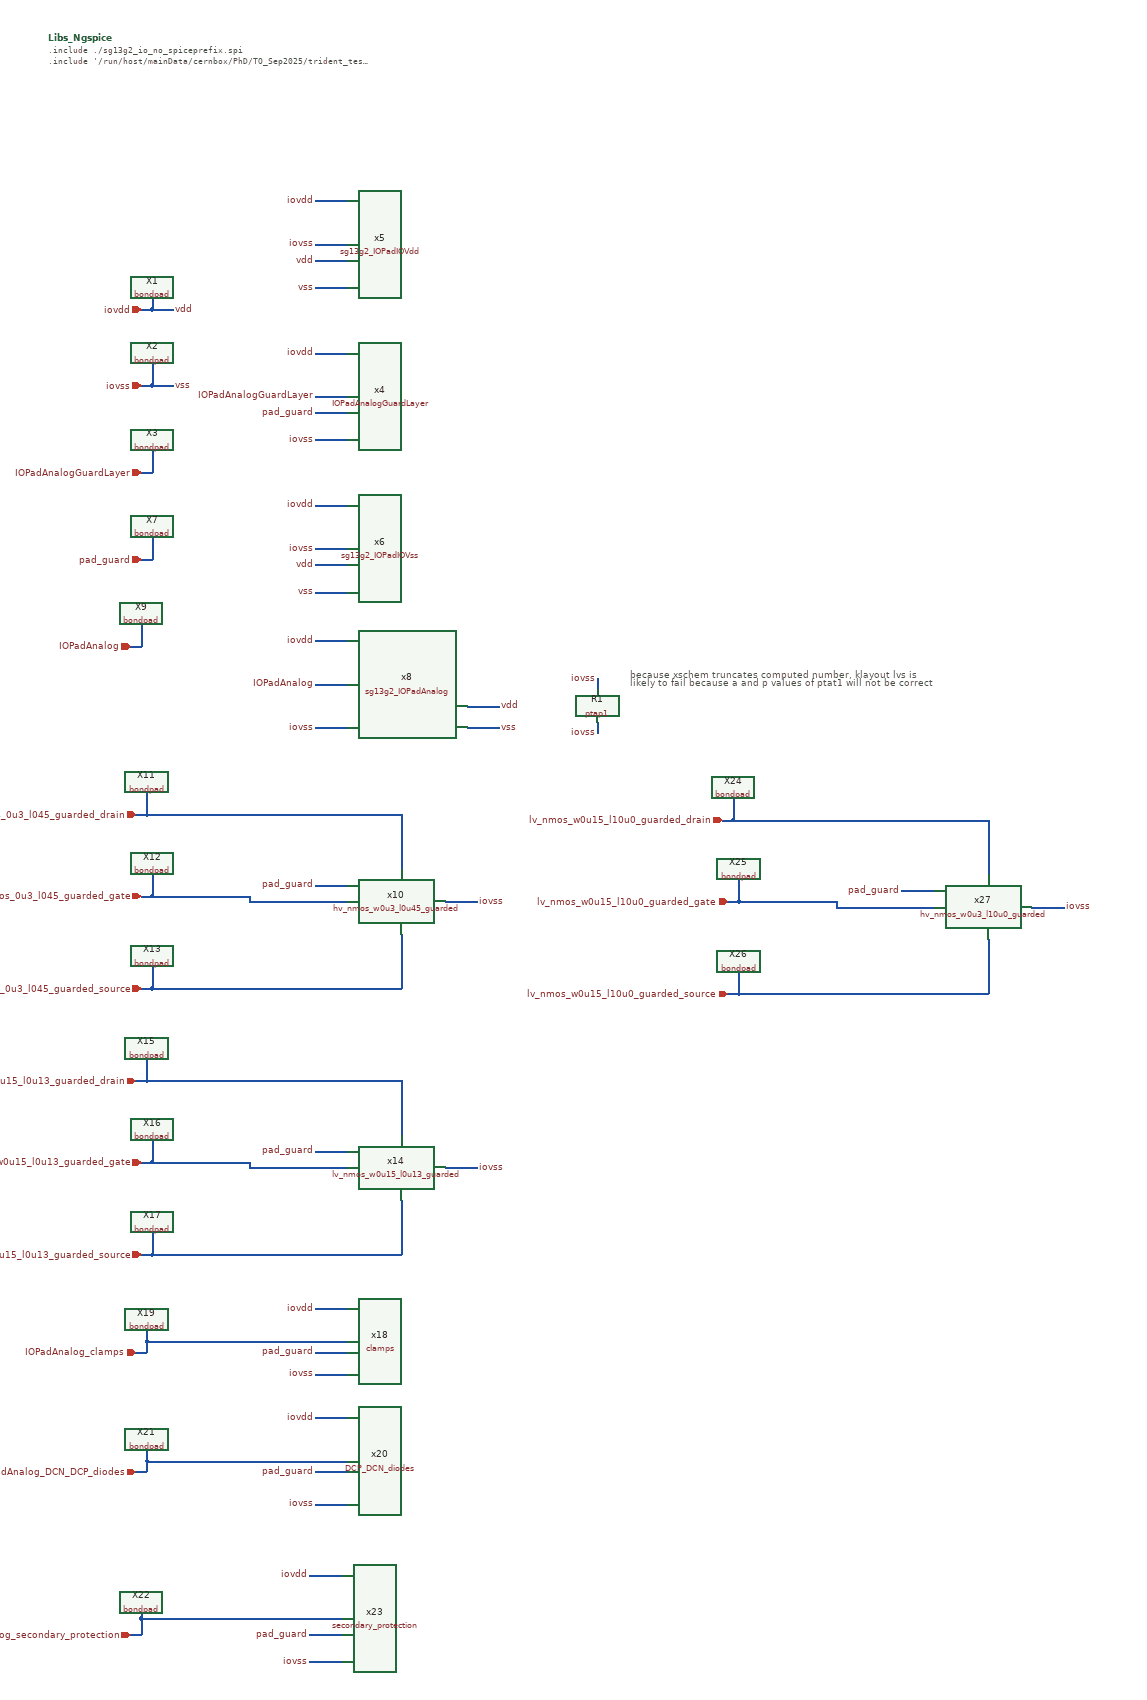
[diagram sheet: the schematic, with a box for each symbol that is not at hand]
v {xschem version=3.4.8RC file_version=1.2}
G {}
K {}
V {}
S {}
F {}
E {}
T {because xschem truncates computed number, klayout lvs is 
likely to fail because a and p values of ptat1 will not be correct} 800 500 0 0 0.4 0.4 {}
N -100 300 -80 300 {lab=pad_guard}
N -80 260 -80 300 {lab=pad_guard}
N -100 140 -80 140 {lab=IOPadAnalogGuardLayer}
N -80 100 -80 140 {lab=IOPadAnalogGuardLayer}
N -100 -20 -80 -20 {lab=iovss}
N -80 -60 -80 -20 {lab=iovss}
N -100 -160 -80 -160 {lab=iovdd}
N -80 -180 -80 -160 {lab=iovdd}
N 220 -360 280 -360 {lab=iovdd}
N 220 -80 280 -80 {lab=iovdd}
N 220 200 280 200 {lab=iovdd}
N 220 -280 280 -280 {lab=iovss}
N 220 80 280 80 {lab=iovss}
N 220 280 280 280 {lab=iovss}
N 220 -250 280 -250 {lab=vdd}
N 220 310 280 310 {lab=vdd}
N 220 -200 280 -200 {lab=vss}
N 220 360 280 360 {lab=vss}
N 220 -0 280 -0 {lab=IOPadAnalogGuardLayer}
N 220 30 280 30 {lab=pad_guard}
N -80 -20 -40 -20 {lab=iovss}
N -80 -160 -40 -160 {lab=iovdd}
N -120 460 -100 460 {lab=IOPadAnalog}
N -100 420 -100 460 {lab=IOPadAnalog}
N 220 450 280 450 {lab=iovdd}
N 220 610 280 610 {lab=iovss}
N 220 530 280 530 {lab=IOPadAnalog}
N 500 570 560 570 {lab=vdd}
N 500 610 560 610 {lab=vss}
N 740 600 740 620 {lab=iovss}
N 740 520 740 540 {lab=iovss}
N 460 930 520 930 {lab=iovss}
N 220 900 280 900 {lab=pad_guard}
N -110 770 -90 770 {lab=hv_nmos_0u3_l045_guarded_drain}
N -90 730 -90 770 {lab=hv_nmos_0u3_l045_guarded_drain}
N -100 920 -80 920 {lab=hv_nmos_0u3_l045_guarded_gate}
N -80 880 -80 920 {lab=hv_nmos_0u3_l045_guarded_gate}
N -100 1090 -80 1090 {lab=hv_nmos_0u3_l045_guarded_source}
N -80 1050 -80 1090 {lab=hv_nmos_0u3_l045_guarded_source}
N -90 770 380 770 {lab=hv_nmos_0u3_l045_guarded_drain}
N 380 770 380 870 {lab=hv_nmos_0u3_l045_guarded_drain}
N -80 1090 380 1090 {lab=hv_nmos_0u3_l045_guarded_source}
N 380 990 380 1090 {lab=hv_nmos_0u3_l045_guarded_source}
N -80 920 100 920 {lab=hv_nmos_0u3_l045_guarded_gate}
N 100 920 100 930 {lab=hv_nmos_0u3_l045_guarded_gate}
N 100 930 280 930 {lab=hv_nmos_0u3_l045_guarded_gate}
N 460 1420 520 1420 {lab=iovss}
N 220 1390 280 1390 {lab=pad_guard}
N -110 1260 -90 1260 {lab=lv_nmos_w0u15_l0u13_guarded_drain}
N -90 1220 -90 1260 {lab=lv_nmos_w0u15_l0u13_guarded_drain}
N -100 1410 -80 1410 {lab=lv_nmos_w0u15_l0u13_guarded_gate}
N -80 1370 -80 1410 {lab=lv_nmos_w0u15_l0u13_guarded_gate}
N -100 1580 -80 1580 {lab=lv_nmos_w0u15_l0u13_guarded_source}
N -80 1540 -80 1580 {lab=lv_nmos_w0u15_l0u13_guarded_source}
N -90 1260 380 1260 {lab=lv_nmos_w0u15_l0u13_guarded_drain}
N 380 1260 380 1360 {lab=lv_nmos_w0u15_l0u13_guarded_drain}
N -80 1580 380 1580 {lab=lv_nmos_w0u15_l0u13_guarded_source}
N 380 1480 380 1580 {lab=lv_nmos_w0u15_l0u13_guarded_source}
N -80 1410 100 1410 {lab=lv_nmos_w0u15_l0u13_guarded_gate}
N 100 1410 100 1420 {lab=lv_nmos_w0u15_l0u13_guarded_gate}
N 100 1420 280 1420 {lab=lv_nmos_w0u15_l0u13_guarded_gate}
N 220 1800 280 1800 {lab=iovss}
N 220 1680 280 1680 {lab=iovdd}
N 220 1760 280 1760 {lab=pad_guard}
N -110 1760 -90 1760 {lab=IOPadAnalog_clamps}
N -90 1740 -90 1760 {lab=IOPadAnalog_clamps}
N -90 1740 280 1740 {lab=IOPadAnalog_clamps}
N -90 1720 -90 1740 {lab=IOPadAnalog_clamps}
N 220 2040 280 2040 {lab=iovss}
N 220 1880 280 1880 {lab=iovdd}
N 220 1980 280 1980 {lab=pad_guard}
N -110 1980 -90 1980 {lab=IOPadAnalog_DCN_DCP_diodes}
N -90 1960 -90 1980 {lab=IOPadAnalog_DCN_DCP_diodes}
N -90 1960 280 1960 {lab=IOPadAnalog_DCN_DCP_diodes}
N -90 1940 -90 1960 {lab=IOPadAnalog_DCN_DCP_diodes}
N 210 2330 270 2330 {lab=iovss}
N 210 2170 270 2170 {lab=iovdd}
N 210 2280 270 2280 {lab=pad_guard}
N -120 2280 -100 2280 {lab=IOPadAnalog_secondary_protection}
N -100 2250 270 2250 {lab=IOPadAnalog_secondary_protection}
N -100 2250 -100 2280 {lab=IOPadAnalog_secondary_protection}
N -100 2240 -100 2250 {lab=IOPadAnalog_secondary_protection}
N 1540 940 1600 940 {lab=iovss}
N 1300 910 1360 910 {lab=pad_guard}
N 970 780 990 780 {lab=lv_nmos_w0u15_l10u0_guarded_drain}
N 990 740 990 780 {lab=lv_nmos_w0u15_l10u0_guarded_drain}
N 980 930 1000 930 {lab=lv_nmos_w0u15_l10u0_guarded_gate}
N 1000 890 1000 930 {lab=lv_nmos_w0u15_l10u0_guarded_gate}
N 980 1100 1000 1100 {lab=lv_nmos_w0u15_l10u0_guarded_source}
N 1000 1060 1000 1100 {lab=lv_nmos_w0u15_l10u0_guarded_source}
N 990 780 1460 780 {lab=lv_nmos_w0u15_l10u0_guarded_drain}
N 1460 780 1460 880 {lab=lv_nmos_w0u15_l10u0_guarded_drain}
N 1000 1100 1460 1100 {lab=lv_nmos_w0u15_l10u0_guarded_source}
N 1460 1000 1460 1100 {lab=lv_nmos_w0u15_l10u0_guarded_source}
N 1000 930 1180 930 {lab=lv_nmos_w0u15_l10u0_guarded_gate}
N 1180 930 1180 940 {lab=lv_nmos_w0u15_l10u0_guarded_gate}
N 1180 940 1360 940 {lab=lv_nmos_w0u15_l10u0_guarded_gate}
C {sg13g2_pr/bondpad.sym} -80 -220 0 0 {name=X1
model=bondpad
spiceprefix=X
size=80u
shape=0
padtype=0
}
C {sg13g2_pr/bondpad.sym} -80 -100 0 0 {name=X2
model=bondpad
spiceprefix=X
size=80u
shape=0
padtype=0
}
C {sg13g2_pr/bondpad.sym} -80 60 0 0 {name=X3
model=bondpad
spiceprefix=X
size=80u
shape=0
padtype=0
}
C {IOPadAnalogGuardLayer.sym} 400 0 0 0 {name=x4}
C {simulator_commands_shown.sym} -270 -660 0 0 {
name=Libs_Ngspice
simulator=ngspice
only_toplevel=false
value="
.include ./sg13g2_io_no_spiceprefix.spi
.include '/run/host/mainData/cernbox/PhD/TO_Sep2025/trident_test_structures/design_data/xschem/fullchip/IOPadAnalogGuardLayer.spice'

"
      }
C {sg13g2_IOPadIOVdd.sym} 400 -280 0 0 {name=x5}
C {sg13g2_IOPadIOVss.sym} 400 280 0 0 {name=x6}
C {sg13g2_pr/bondpad.sym} -80 220 0 0 {name=X7
model=bondpad
spiceprefix=X
size=80u
shape=0
padtype=0
}
C {lab_pin.sym} 220 -360 0 0 {name=p5 sig_type=std_logic lab=iovdd}
C {lab_pin.sym} 220 -80 0 0 {name=p6 sig_type=std_logic lab=iovdd}
C {lab_pin.sym} 220 200 0 0 {name=p7 sig_type=std_logic lab=iovdd}
C {lab_pin.sym} 220 -280 0 0 {name=p8 sig_type=std_logic lab=iovss}
C {lab_pin.sym} 220 80 0 0 {name=p9 sig_type=std_logic lab=iovss}
C {lab_pin.sym} 220 280 0 0 {name=p10 sig_type=std_logic lab=iovss}
C {lab_pin.sym} 220 -250 0 0 {name=p11 sig_type=std_logic lab=vdd}
C {lab_pin.sym} 220 310 0 0 {name=p12 sig_type=std_logic lab=vdd}
C {lab_pin.sym} 220 -200 0 0 {name=p13 sig_type=std_logic lab=vss}
C {lab_pin.sym} 220 360 0 0 {name=p14 sig_type=std_logic lab=vss}
C {lab_pin.sym} 220 0 0 0 {name=p15 sig_type=std_logic lab=IOPadAnalogGuardLayer}
C {lab_pin.sym} 220 30 0 0 {name=p16 sig_type=std_logic lab=pad_guard}
C {iopin.sym} -100 -160 2 0 {name=p17 lab=iovdd}
C {iopin.sym} -100 -20 2 0 {name=p18 lab=iovss}
C {iopin.sym} -100 140 2 0 {name=p19 lab=IOPadAnalogGuardLayer}
C {iopin.sym} -100 300 2 0 {name=p20 lab=pad_guard}
C {lab_pin.sym} -40 -20 2 0 {name=p1 sig_type=std_logic lab=vss}
C {lab_pin.sym} -40 -160 2 0 {name=p2 sig_type=std_logic lab=vdd}
C {sg13g2_IOPadAnalog.sym} 400 530 0 0 {name=x8}
C {sg13g2_pr/bondpad.sym} -100 380 0 0 {name=X9
model=bondpad
spiceprefix=X
size=80u
shape=0
padtype=0
}
C {iopin.sym} -120 460 2 0 {name=p3 lab=IOPadAnalog}
C {lab_pin.sym} 220 450 0 0 {name=p4 sig_type=std_logic lab=iovdd}
C {lab_pin.sym} 220 610 0 0 {name=p21 sig_type=std_logic lab=iovss}
C {lab_pin.sym} 220 530 0 0 {name=p22 sig_type=std_logic lab=IOPadAnalog}
C {lab_pin.sym} 560 570 0 1 {name=p23 sig_type=std_logic lab=vdd}
C {lab_pin.sym} 560 610 0 1 {name=p24 sig_type=std_logic lab=vss}
C {sg13g2_pr/ptap1.sym} 740 570 0 0 {name=R1
model=ptap1
spiceprefix=X
w=3.34822224741240814064559564809029515308661819237201e-3
l=6.28775258759185935440435190970484691338180762799331e-6

}
C {lab_pin.sym} 740 520 0 0 {name=p25 sig_type=std_logic lab=iovss}
C {lab_pin.sym} 740 620 0 0 {name=p26 sig_type=std_logic lab=iovss}
C {/run/host/mainData/cernbox/PhD/TO_Sep2025/trident_test_structures/design_data/xschem/transistor_characterization/hv_nmos_w0u3_l0u45_guarded/hv_nmos_w0u3_l0u45_guarded.sym} 360 930 0 0 {name=x10}
C {lab_pin.sym} 520 930 0 1 {name=p27 sig_type=std_logic lab=iovss}
C {lab_pin.sym} 220 900 0 0 {name=p28 sig_type=std_logic lab=pad_guard}
C {sg13g2_pr/bondpad.sym} -90 690 0 0 {name=X11
model=bondpad
spiceprefix=X
size=80u
shape=0
padtype=0
}
C {iopin.sym} -110 770 2 0 {name=p29 lab=hv_nmos_0u3_l045_guarded_drain}
C {sg13g2_pr/bondpad.sym} -80 840 0 0 {name=X12
model=bondpad
spiceprefix=X
size=80u
shape=0
padtype=0
}
C {iopin.sym} -100 920 2 0 {name=p30 lab=hv_nmos_0u3_l045_guarded_gate}
C {sg13g2_pr/bondpad.sym} -80 1010 0 0 {name=X13
model=bondpad
spiceprefix=X
size=80u
shape=0
padtype=0
}
C {iopin.sym} -100 1090 2 0 {name=p31 lab=hv_nmos_0u3_l045_guarded_source}
C {lab_pin.sym} 520 1420 0 1 {name=p32 sig_type=std_logic lab=iovss}
C {lab_pin.sym} 220 1390 0 0 {name=p33 sig_type=std_logic lab=pad_guard}
C {sg13g2_pr/bondpad.sym} -90 1180 0 0 {name=X15
model=bondpad
spiceprefix=X
size=80u
shape=0
padtype=0
}
C {iopin.sym} -110 1260 2 0 {name=p34 lab=lv_nmos_w0u15_l0u13_guarded_drain}
C {sg13g2_pr/bondpad.sym} -80 1330 0 0 {name=X16
model=bondpad
spiceprefix=X
size=80u
shape=0
padtype=0
}
C {iopin.sym} -100 1410 2 0 {name=p35 lab=lv_nmos_w0u15_l0u13_guarded_gate}
C {sg13g2_pr/bondpad.sym} -80 1500 0 0 {name=X17
model=bondpad
spiceprefix=X
size=80u
shape=0
padtype=0
}
C {iopin.sym} -100 1580 2 0 {name=p36 lab=lv_nmos_w0u15_l0u13_guarded_source}
C {/run/host/mainData/cernbox/PhD/TO_Sep2025/trident_test_structures/design_data/xschem/transistor_characterization/lv_nmos_w0u15_l0u13_guarded/lv_nmos_w0u15_l0u13_guarded.sym} 360 1420 0 0 {name=x14}
C {lab_pin.sym} 220 1800 2 1 {name=p37 sig_type=std_logic lab=iovss}
C {lab_pin.sym} 220 1680 2 1 {name=p38 sig_type=std_logic lab=iovdd}
C {lab_pin.sym} 220 1760 0 0 {name=p39 sig_type=std_logic lab=pad_guard}
C {sg13g2_pr/bondpad.sym} -90 1680 0 0 {name=X19
model=bondpad
spiceprefix=X
size=80u
shape=0
padtype=0
}
C {iopin.sym} -110 1760 2 0 {name=p40 lab=IOPadAnalog_clamps}
C {lab_pin.sym} 220 2040 2 1 {name=p41 sig_type=std_logic lab=iovss}
C {lab_pin.sym} 220 1880 2 1 {name=p42 sig_type=std_logic lab=iovdd}
C {lab_pin.sym} 220 1980 0 0 {name=p43 sig_type=std_logic lab=pad_guard}
C {sg13g2_pr/bondpad.sym} -90 1900 0 0 {name=X21
model=bondpad
spiceprefix=X
size=80u
shape=0
padtype=0
}
C {iopin.sym} -110 1980 2 0 {name=p44 lab=IOPadAnalog_DCN_DCP_diodes
}
C {/run/host/mainData/cernbox/PhD/TO_Sep2025/trident_test_structures/design_data/xschem/IOPadAnalog_submodules/clamps.sym} 360 1740 0 0 {name=x18}
C {/run/host/mainData/cernbox/PhD/TO_Sep2025/trident_test_structures/design_data/xschem/IOPadAnalog_submodules/DCP_DCN_diodes.sym} 360 1960 0 0 {name=x20}
C {lab_pin.sym} 210 2330 2 1 {name=p45 sig_type=std_logic lab=iovss}
C {lab_pin.sym} 210 2170 2 1 {name=p46 sig_type=std_logic lab=iovdd}
C {lab_pin.sym} 210 2280 0 0 {name=p47 sig_type=std_logic lab=pad_guard}
C {sg13g2_pr/bondpad.sym} -100 2200 0 0 {name=X22
model=bondpad
spiceprefix=X
size=80u
shape=0
padtype=0
}
C {iopin.sym} -120 2280 2 0 {name=p48 lab=IOPadAnalog_secondary_protection
}
C {/run/host/mainData/cernbox/PhD/TO_Sep2025/trident_test_structures/design_data/xschem/IOPadAnalog_submodules/secondary_protection.sym} 390 2250 0 0 {name=x23}
C {lab_pin.sym} 1600 940 0 1 {name=p49 sig_type=std_logic lab=iovss}
C {lab_pin.sym} 1300 910 0 0 {name=p50 sig_type=std_logic lab=pad_guard}
C {sg13g2_pr/bondpad.sym} 990 700 0 0 {name=X24
model=bondpad
spiceprefix=X
size=80u
shape=0
padtype=0
}
C {iopin.sym} 970 780 2 0 {name=p51 lab=lv_nmos_w0u15_l10u0_guarded_drain}
C {sg13g2_pr/bondpad.sym} 1000 850 0 0 {name=X25
model=bondpad
spiceprefix=X
size=80u
shape=0
padtype=0
}
C {iopin.sym} 980 930 2 0 {name=p52 lab=lv_nmos_w0u15_l10u0_guarded_gate}
C {sg13g2_pr/bondpad.sym} 1000 1020 0 0 {name=X26
model=bondpad
spiceprefix=X
size=80u
shape=0
padtype=0
}
C {iopin.sym} 980 1100 2 0 {name=p53 lab=lv_nmos_w0u15_l10u0_guarded_source}
C {/run/host/mainData/cernbox/PhD/TO_Sep2025/trident_test_structures/design_data/xschem/transistor_characterization/hv_nmos_w0u3_l10u0_guarded/hv_nmos_w0u3_l10u0_guarded.sym} 1440 940 0 0 {name=x27}
